VERSION 5.7 ;
  NOWIREEXTENSIONATPIN ON ;
  DIVIDERCHAR "/" ;
  BUSBITCHARS "[]" ;
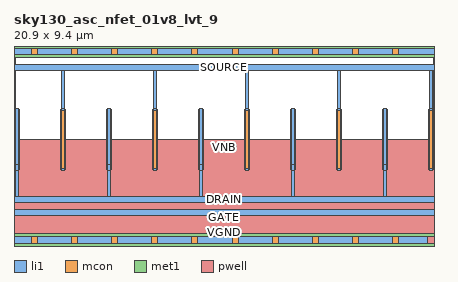
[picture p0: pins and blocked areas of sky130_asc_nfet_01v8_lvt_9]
MACRO sky130_asc_nfet_01v8_lvt_9
  CLASS CORE ;
  FOREIGN sky130_asc_nfet_01v8_lvt_9 ;
  ORIGIN 0.000 0.000 ;
  SIZE 20.900 BY 9.400 ;
  SITE unitasc ;
  PIN GATE
    DIRECTION INOUT ;
    ANTENNAGATEAREA 54.000000 ;
    PORT
      LAYER li1 ;
        RECT 0.000 1.220 20.900 1.520 ;
    END
  END GATE
  PIN SOURCE
    DIRECTION INOUT ;
    ANTENNADIFFAREA 4.350000 ;
    PORT
      LAYER li1 ;
        RECT 0.000 8.450 20.900 8.750 ;
        RECT 2.345 6.520 2.515 8.450 ;
        RECT 6.925 6.520 7.095 8.450 ;
        RECT 11.505 6.520 11.675 8.450 ;
        RECT 16.085 6.520 16.255 8.450 ;
        RECT 20.665 6.520 20.835 8.450 ;
        RECT 2.345 6.430 2.520 6.520 ;
        RECT 6.925 6.430 7.100 6.520 ;
        RECT 11.505 6.430 11.680 6.520 ;
        RECT 16.085 6.430 16.260 6.520 ;
        RECT 20.665 6.430 20.840 6.520 ;
        RECT 2.350 3.480 2.520 6.430 ;
        RECT 6.930 3.480 7.100 6.430 ;
        RECT 11.510 3.480 11.680 6.430 ;
        RECT 16.090 3.480 16.260 6.430 ;
        RECT 20.670 3.480 20.840 6.430 ;
      LAYER mcon ;
        RECT 2.350 3.560 2.520 6.440 ;
        RECT 6.930 3.560 7.100 6.440 ;
        RECT 11.510 3.560 11.680 6.440 ;
        RECT 16.090 3.560 16.260 6.440 ;
        RECT 20.670 3.560 20.840 6.440 ;
      LAYER met1 ;
        RECT 2.320 3.500 2.550 6.500 ;
        RECT 6.900 3.500 7.130 6.500 ;
        RECT 11.480 3.500 11.710 6.500 ;
        RECT 16.060 3.500 16.290 6.500 ;
        RECT 20.640 3.500 20.870 6.500 ;
    END
  END SOURCE
  PIN DRAIN
    DIRECTION INOUT ;
    ANTENNADIFFAREA 4.350000 ;
    PORT
      LAYER li1 ;
        RECT 0.060 3.770 0.230 6.520 ;
        RECT 4.640 3.770 4.810 6.520 ;
        RECT 9.220 3.770 9.390 6.520 ;
        RECT 13.800 3.770 13.970 6.520 ;
        RECT 18.380 3.770 18.550 6.520 ;
        RECT 0.055 3.480 0.230 3.770 ;
        RECT 4.635 3.480 4.810 3.770 ;
        RECT 9.215 3.480 9.390 3.770 ;
        RECT 13.795 3.480 13.970 3.770 ;
        RECT 18.375 3.480 18.550 3.770 ;
        RECT 0.055 2.150 0.225 3.480 ;
        RECT 4.635 2.150 4.805 3.480 ;
        RECT 9.215 2.150 9.385 3.480 ;
        RECT 13.795 2.150 13.965 3.480 ;
        RECT 18.375 2.150 18.545 3.480 ;
        RECT 0.000 1.850 20.900 2.150 ;
      LAYER mcon ;
        RECT 0.060 3.560 0.230 6.440 ;
        RECT 4.640 3.560 4.810 6.440 ;
        RECT 9.220 3.560 9.390 6.440 ;
        RECT 13.800 3.560 13.970 6.440 ;
        RECT 18.380 3.560 18.550 6.440 ;
      LAYER met1 ;
        RECT 0.030 3.500 0.260 6.500 ;
        RECT 4.610 3.500 4.840 6.500 ;
        RECT 9.190 3.500 9.420 6.500 ;
        RECT 13.770 3.500 14.000 6.500 ;
        RECT 18.350 3.500 18.580 6.500 ;
    END
  END DRAIN
  PIN VNB
    DIRECTION INOUT ;
    USE GROUND ;
    PORT
      LAYER pwell ;
        RECT 0.000 0.150 20.900 5.000 ;
        RECT 20.600 -0.150 20.900 0.150 ;
    END
  END VNB
  PIN VPWR
    DIRECTION INOUT ;
    USE POWER ;
    PORT
      LAYER li1 ;
        RECT 0.000 9.250 20.900 9.550 ;
      LAYER mcon ;
        RECT 0.850 9.250 1.150 9.550 ;
        RECT 2.850 9.250 3.150 9.550 ;
        RECT 4.850 9.250 5.150 9.550 ;
        RECT 6.850 9.250 7.150 9.550 ;
        RECT 8.850 9.250 9.150 9.550 ;
        RECT 10.850 9.250 11.150 9.550 ;
        RECT 12.850 9.250 13.150 9.550 ;
        RECT 14.850 9.250 15.150 9.550 ;
        RECT 16.850 9.250 17.150 9.550 ;
        RECT 18.850 9.250 19.150 9.550 ;
      LAYER met1 ;
        RECT 0.000 9.100 20.900 9.700 ;
    END
  END VPWR
  PIN VGND
    DIRECTION INOUT ;
    USE GROUND ;
    PORT
      LAYER li1 ;
        RECT 0.000 -0.150 20.900 0.150 ;
      LAYER mcon ;
        RECT 0.850 -0.150 1.150 0.150 ;
        RECT 2.850 -0.150 3.150 0.150 ;
        RECT 4.850 -0.150 5.150 0.150 ;
        RECT 6.850 -0.150 7.150 0.150 ;
        RECT 8.850 -0.150 9.150 0.150 ;
        RECT 10.850 -0.150 11.150 0.150 ;
        RECT 12.850 -0.150 13.150 0.150 ;
        RECT 14.850 -0.150 15.150 0.150 ;
        RECT 16.850 -0.150 17.150 0.150 ;
        RECT 18.850 -0.150 19.150 0.150 ;
      LAYER met1 ;
        RECT 0.000 -0.300 20.900 0.300 ;
    END
  END VGND
END sky130_asc_nfet_01v8_lvt_9
END LIBRARY

